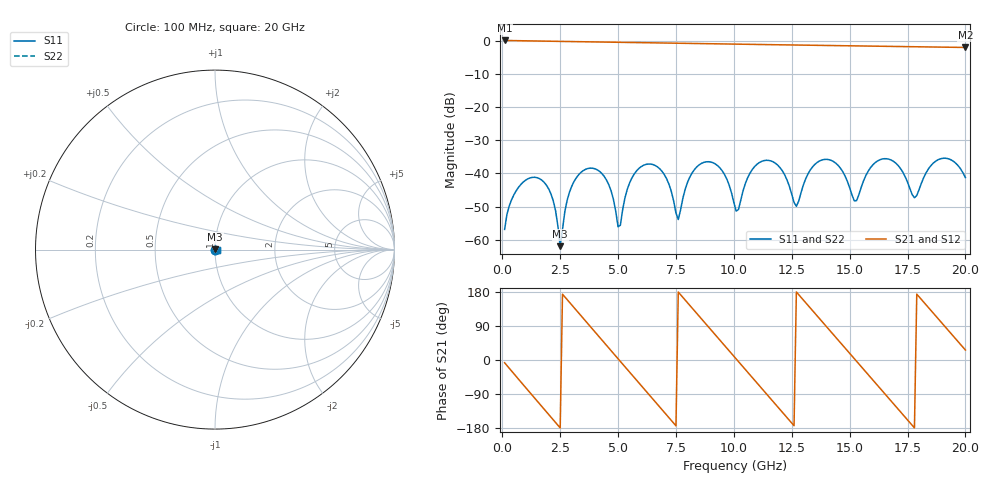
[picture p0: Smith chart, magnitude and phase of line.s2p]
# Hz S RI R 50.0
!freq ReS11 ImS11 ReS21 ImS21 ReS12 ImS12 ReS22 ImS22
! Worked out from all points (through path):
!   200 points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, 100 MHz to 20 GHz, reference 50 ohm
!   highest |S21| = 0.05 dB at 100 MHz (marker M1); lowest = -2.1 dB at 20 GHz (marker M2)
!   group delay of S21, straight-line fit = 196 ps
!   lowest |S11| = -61.9 dB at 2.5 GHz (marker M3), VSWR 1.00, Z = 50.1 + j0.0573 ohm
!   |S11| at or under -10 dB: start of sweep to end of sweep
!   |S22| runs from -61.9 to -35.4 dB; largest |S21 - S12| = 4.7e-16
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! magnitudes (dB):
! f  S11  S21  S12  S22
! 100 MHz  -56.9  0.1  0.1  -56.9
! 1.5 GHz  -41.3  -0.1  -0.1  -41.3
! 2.1 GHz  -46.1  -0.2  -0.2  -46.1
! 2.5 GHz  -61.9  -0.2  -0.2  -61.9
! 2.9 GHz  -45.7  -0.3  -0.3  -45.7
! 3.5 GHz  -39.1  -0.3  -0.3  -39.1
! 4.5 GHz  -42.0  -0.5  -0.5  -42.0
! 5 GHz  -56.1  -0.5  -0.5  -56.1
! 5.7 GHz  -40.2  -0.6  -0.6  -40.2
! 6.8 GHz  -38.6  -0.7  -0.7  -38.6
! 7.6 GHz  -53.9  -0.8  -0.8  -53.9
! 8.8 GHz  -36.5  -0.9  -0.9  -36.5
! 10.1 GHz  -51.4  -1.1  -1.1  -51.4
! 11.1 GHz  -36.7  -1.2  -1.2  -36.7
! 12.7 GHz  -49.9  -1.3  -1.3  -49.9
! 13.4 GHz  -38.0  -1.4  -1.4  -38.0
! 14.4 GHz  -36.9  -1.5  -1.5  -36.9
! 15.3 GHz  -48.2  -1.6  -1.6  -48.2
! 16.7 GHz  -35.7  -1.7  -1.7  -35.7
! 17.8 GHz  -47.3  -1.8  -1.8  -47.3
! 18.9 GHz  -35.6  -1.9  -1.9  -35.6
! 20 GHz  -41.2  -2.1  -2.1  -41.2
